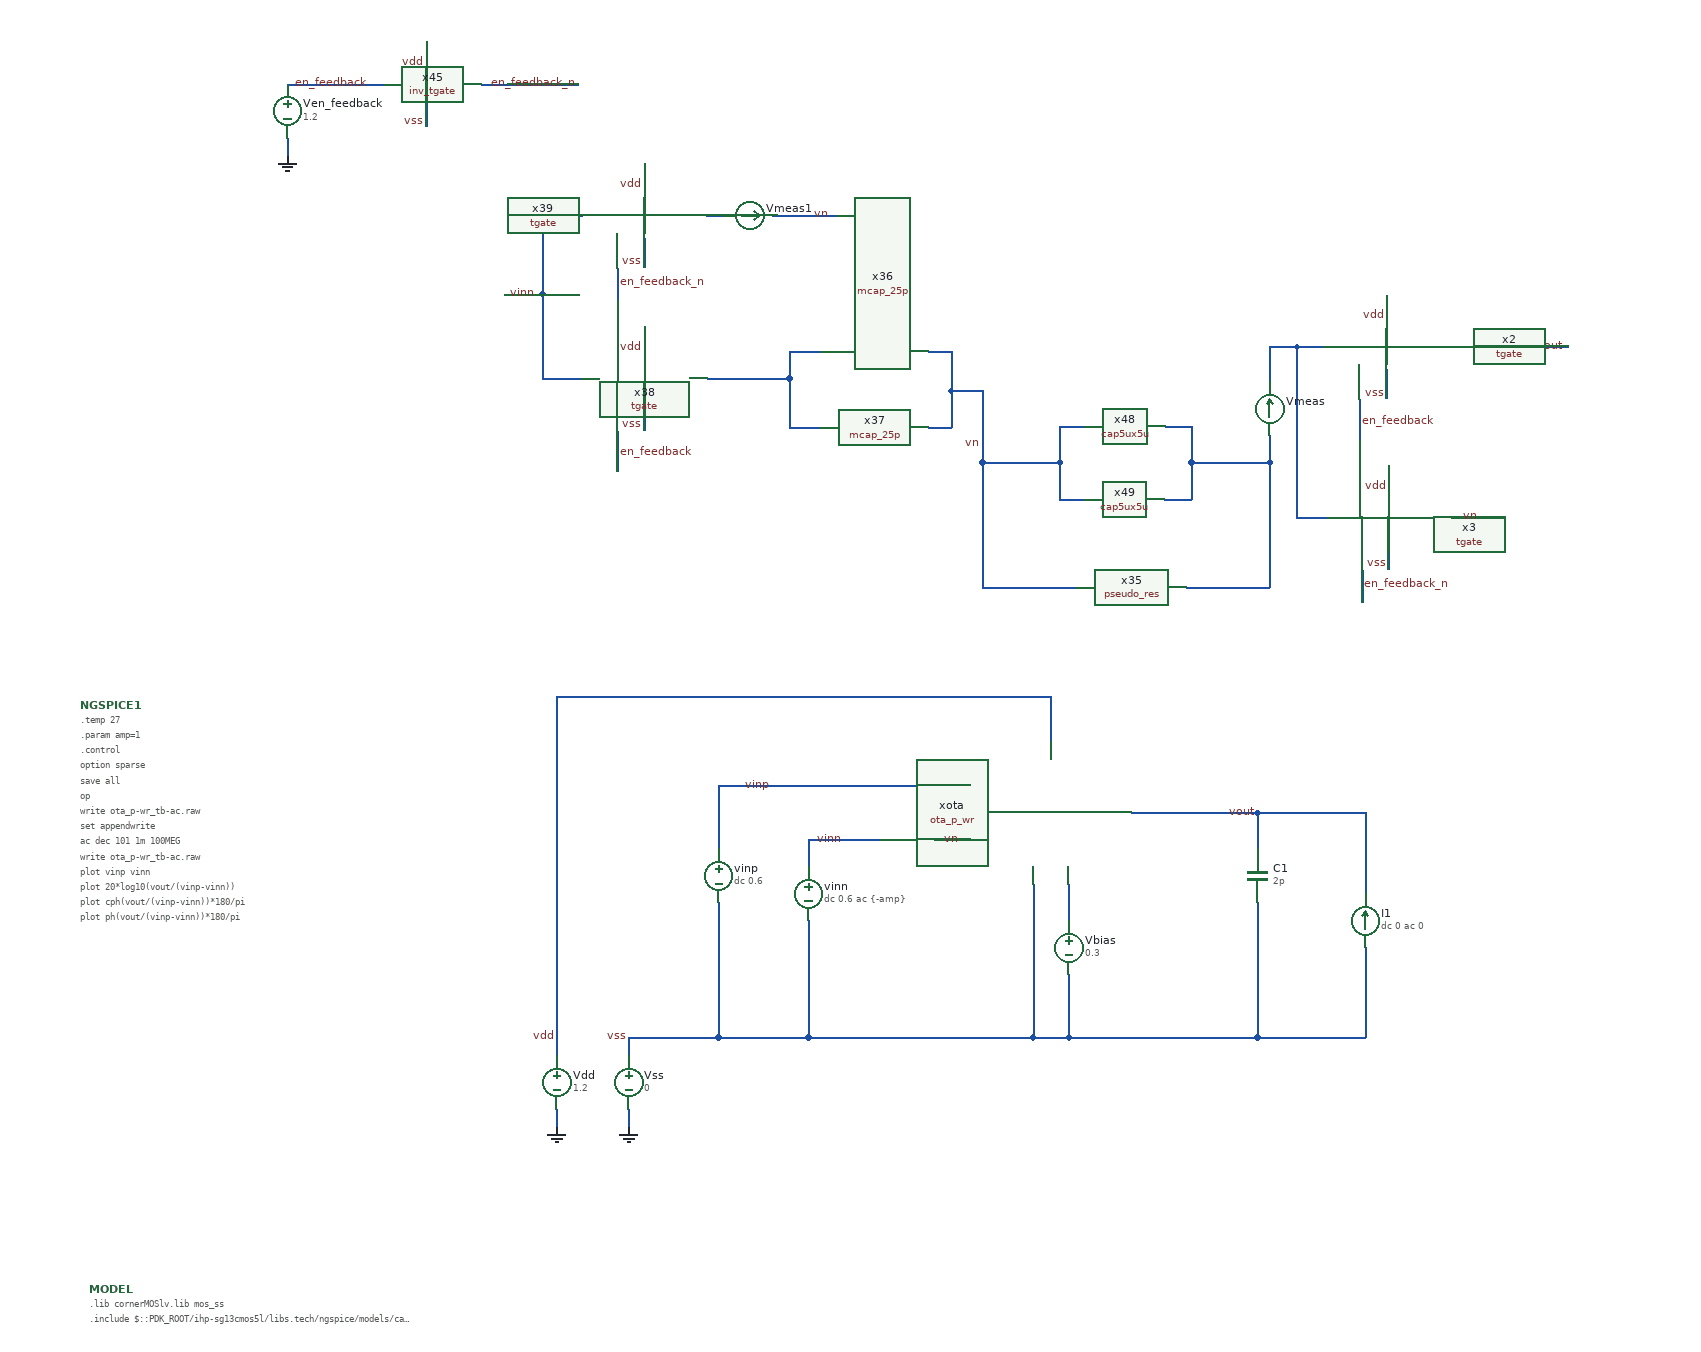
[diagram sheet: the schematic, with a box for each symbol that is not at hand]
v {xschem version=3.4.8RC file_version=1.3}
G {}
K {}
V {}
S {}
F {}
E {}
N 520 -300 520 -280 {
lab=GND}
N 600 -300 600 -280 {
lab=GND}
N 600 -380 600 -360 {
lab=vss}
N 1050 -550 1050 -380 {
lab=vss}
N 1300 -530 1300 -380 {
lab=vss}
N 1300 -630 1300 -590 {
lab=vout}
N 800 -600 880 -600 {
lab=vinn}
N 1070 -760 1070 -710 {
lab=vdd}
N 520 -760 1070 -760 {
lab=vdd}
N 520 -760 520 -360 {
lab=vdd}
N 1420 -480 1420 -380 {lab=vss}
N 1300 -380 1420 -380 {lab=vss}
N 1420 -630 1420 -540 {lab=vout}
N 1300 -630 1420 -630 {lab=vout}
N 800 -380 1050 -380 {
lab=vss}
N 800 -600 800 -570 {lab=vinn}
N 800 -510 800 -380 {lab=vss}
N 1090 -550 1090 -510 {lab=#net1}
N 1090 -380 1300 -380 {
lab=vss}
N 1090 -450 1090 -380 {
lab=vss}
N 1050 -380 1090 -380 {
lab=vss}
N 1160 -630 1300 -630 {lab=vout}
N 700 -660 980 -660 {lab=vinp}
N 700 -660 700 -590 {lab=vinp}
N 700 -530 700 -380 {lab=vss}
N 600 -380 700 -380 {
lab=vss}
N 700 -380 800 -380 {
lab=vss}
N 940 -600 980 -600 {lab=vn}
N 778.75 -1058.75 813.75 -1058.75 {lab=#net2}
N 933.75 -1058.75 958.75 -1058.75 {lab=vn}
N 933.75 -1143.75 958.75 -1143.75 {lab=vn}
N 778.75 -1113.75 778.75 -1058.75 {lab=#net2}
N 778.75 -1143.75 778.75 -1113.75 {lab=#net2}
N 993.75 -881.25 1098.75 -881.25 {lab=vn}
N 1221.25 -881.25 1313.75 -881.25 {lab=#net3}
N 1313.75 -1020 1313.75 -881.25 {lab=#net3}
N 993.75 -1020 993.75 -881.25 {lab=vn}
N 958.75 -1100 993.75 -1100 {lab=vn}
N 958.75 -1100 958.75 -1058.75 {lab=vn}
N 958.75 -1143.75 958.75 -1100 {lab=vn}
N 503.75 -1295 548.75 -1295 {lab=vinn}
N 503.75 -1207.5 503.75 -1113.75 {lab=vinn}
N 503.75 -1113.75 547.5 -1113.75 {lab=vinn}
N 461.25 -1207.5 503.75 -1207.5 {lab=vinn}
N 503.75 -1295 503.75 -1207.5 {lab=vinn}
N 587.5 -1236.25 587.5 -1200 {lab=en_feedback_n}
N 587.5 -1055 587.5 -1010 {lab=en_feedback}
N 617.5 -1088.75 617.5 -1056.25 {lab=vss}
N 617.5 -1171.25 617.5 -1138.75 {lab=vdd}
N 617.5 -1270 617.5 -1237.5 {lab=vss}
N 617.5 -1352.5 617.5 -1320 {lab=vdd}
N 220 -1441.25 327.5 -1441.25 {lab=en_feedback}
N 436.25 -1441.25 543.75 -1441.25 {lab=en_feedback_n}
N 375 -1488.75 375 -1456.25 {lab=vdd}
N 375 -1426.25 375 -1393.75 {lab=vss}
N 1197.5 -1060 1226.25 -1060 {lab=#net3}
N 1226.25 -1020 1226.25 -978.75 {lab=#net3}
N 1196.25 -978.75 1226.25 -978.75 {lab=#net3}
N 1080 -978.75 1107.5 -978.75 {lab=vn}
N 1080 -1020 1080 -978.75 {lab=vn}
N 1080 -1060 1107.5 -1060 {lab=vn}
N 1226.25 -1060 1226.25 -1020 {lab=#net3}
N 1080 -1060 1080 -1020 {lab=vn}
N 993.75 -1100 993.75 -1020 {lab=vn}
N 220 -1381.25 220 -1361.25 {
lab=GND}
N 993.75 -1020 1080 -1020 {lab=vn}
N 1226.25 -1020 1313.75 -1020 {lab=#net3}
N 760 -1295 831.25 -1295 {lab=vn}
N 686.25 -1295 705 -1295 {lab=#net4}
N 687.5 -1113.75 778.75 -1113.75 {lab=#net2}
N 1413.75 -1090 1413.75 -1045 {lab=en_feedback}
N 1443.75 -1123.75 1443.75 -1091.25 {lab=vss}
N 1443.75 -1206.25 1443.75 -1173.75 {lab=vdd}
N 1313.75 -1050 1313.75 -1020 {lab=#net3}
N 1343.75 -1148.75 1373.75 -1148.75 {lab=#net5}
N 1313.75 -1148.75 1313.75 -1110 {lab=#net5}
N 1513.75 -1148.75 1646.25 -1148.75 {lab=vout}
N 1416.25 -900 1416.25 -863.75 {lab=en_feedback_n}
N 1446.25 -933.75 1446.25 -901.25 {lab=vss}
N 1446.25 -1016.25 1446.25 -983.75 {lab=vdd}
N 1343.75 -958.75 1377.5 -958.75 {lab=#net5}
N 1343.75 -1148.75 1343.75 -958.75 {lab=#net5}
N 1313.75 -1148.75 1343.75 -1148.75 {lab=#net5}
N 1516.25 -958.75 1555 -958.75 {lab=vn}
N 778.75 -1143.75 813.75 -1143.75 {lab=#net2}
C {devices/code_shown.sym} 0 -100 0 0 {name=MODEL only_toplevel=true
format="tcleval( @value )"
value=".lib cornerMOSlv.lib mos_ss
.include $::PDK_ROOT/ihp-sg13cmos5l/libs.tech/ngspice/models/cap_mfringe.lib
"}
C {devices/vsource.sym} 520 -330 0 0 {name=Vdd value=1.2}
C {devices/gnd.sym} 520 -280 0 0 {name=l3 lab=GND}
C {devices/title.sym} 160 -30 0 0 {name=l5 author="(c) 2024-2025 Harald Pretl, Apache-2.0 license"}
C {devices/launcher.sym} 680 -160 0 0 {name=h2
descr="simulate" 
tclcommand="xschem save; xschem netlist; xschem simulate"
}
C {devices/launcher.sym} 920 -160 0 0 {name=h3
descr="annotate OP" 
tclcommand="set show_hidden_texts 1; xschem annotate_op"
}
C {devices/lab_pin.sym} 520 -380 0 0 {name=p2 sig_type=std_logic lab=vdd}
C {ota_p_wr.sym} 1050 -630 0 0 {name=xota}
C {devices/vsource.sym} 600 -330 0 0 {name=Vss value=0}
C {devices/gnd.sym} 600 -280 0 0 {name=l1 lab=GND}
C {devices/lab_pin.sym} 600 -380 0 0 {name=p1 sig_type=std_logic lab=vss}
C {devices/capa.sym} 1300 -560 0 0 {name=C1
value=2p}
C {devices/lab_wire.sym} 1300 -630 0 0 {name=p3 sig_type=std_logic lab=vout}
C {devices/lab_wire.sym} 760 -660 0 0 {name=p4 sig_type=std_logic lab=vinp}
C {devices/spice_probe.sym} 820 -660 0 0 {name=p5 attrs=""}
C {devices/spice_probe.sym} 1180 -630 0 0 {name=p6 attrs=""}
C {isource.sym} 1420 -510 2 0 {name=I1 value="dc 0 ac 0"}
C {devices/lab_wire.sym} 840 -600 0 0 {name=p7 sig_type=std_logic lab=vinn}
C {devices/code_shown.sym} -10 -750 0 0 {name=NGSPICE1 only_toplevel=true 
value="
.temp 27
.param amp=1
.control
option sparse
save all
op
write ota_p-wr_tb-ac.raw
set appendwrite

ac dec 101 1m 100MEG
write ota_p-wr_tb-ac.raw
plot vinp vinn
plot 20*log10(vout/(vinp-vinn))
plot cph(vout/(vinp-vinn))*180/pi
plot ph(vout/(vinp-vinn))*180/pi

meas ac dcgain MAX vmag(vout) FROM=1m TO=100k
*let f3db = dcgain/sqrt(2)
*meas ac fbw WHEN vmag(vout)=f3db FALL=1
*let gainerror=(dcgain-1)/1
*print 20*log10(dcgain)
*print gaindb
*print fbw
*print gainerror

noise v(vout) v(vinp) dec 101 1m 1MEG
print onoise_total
print inoise_total


.endc
"}
C {devices/vsource.sym} 800 -540 0 0 {name=vinn value="dc 0.6 ac \{-amp\}"}
C {devices/vsource.sym} 1090 -480 0 0 {name=Vbias value=0.3}
C {devices/vsource.sym} 700 -560 0 0 {name=vinp value="dc 0.6"}
C {devices/lab_wire.sym} 970 -600 0 0 {name=p8 sig_type=std_logic lab=vn}
C {pseudo_res.sym} 1153.75 -883.75 0 0 {name=x35}
C {mcap_25p.sym} 873.75 -1148.75 3 0 {name=x36}
C {mcap_25p.sym} 873.75 -1063.75 3 0 {name=x37}
C {lab_wire.sym} 1642.5 -1148.75 0 0 {name=p124 sig_type=std_logic lab=vout
}
C {tgate.sym} 617.5 -1111.25 0 0 {name=x38}
C {tgate.sym} 617.5 -1292.5 0 0 {name=x39}
C {lab_wire.sym} 993.75 -1040 1 0 {name=p123 sig_type=std_logic lab=vn
}
C {lab_wire.sym} 825 -1295 0 0 {name=p125 sig_type=std_logic lab=vn
}
C {lab_wire.sym} 587.5 -1030 2 0 {name=p130 sig_type=std_logic lab=en_feedback}
C {lab_wire.sym} 587.5 -1220 2 0 {name=p131 sig_type=std_logic lab=en_feedback_n}
C {lab_wire.sym} 617.5 -1147.5 1 0 {name=p138 sig_type=std_logic lab=vdd
}
C {lab_wire.sym} 617.5 -1061.25 1 0 {name=p139 sig_type=std_logic lab=vss
}
C {lab_wire.sym} 617.5 -1328.75 1 0 {name=p140 sig_type=std_logic lab=vdd
}
C {lab_wire.sym} 617.5 -1242.5 1 0 {name=p141 sig_type=std_logic lab=vss
}
C {inv_tgate.sym} 367.5 -1440 0 0 {name=x45}
C {lab_wire.sym} 226.25 -1441.25 2 0 {name=p142 sig_type=std_logic lab=en_feedback}
C {lab_wire.sym} 443.75 -1441.25 2 0 {name=p143 sig_type=std_logic lab=en_feedback_n}
C {lab_wire.sym} 375 -1465 1 0 {name=p144 sig_type=std_logic lab=vdd
}
C {lab_wire.sym} 375 -1398.75 1 0 {name=p145 sig_type=std_logic lab=vss
}
C {cap5ux5u.sym} 1157.5 -1060 1 0 {name=x48}
C {cap5ux5u.sym} 1157.5 -978.75 1 0 {name=x49}
C {lab_wire.sym} 465 -1207.5 2 0 {name=p9 sig_type=std_logic lab=vinn
}
C {devices/vsource.sym} 220 -1411.25 0 0 {name=Ven_feedback value=1.2}
C {devices/gnd.sym} 220 -1361.25 0 0 {name=l2 lab=GND}
C {ammeter.sym} 1313.75 -1080 2 0 {name=Vmeas savecurrent=true spice_ignore=0}
C {ammeter.sym} 735 -1295 3 0 {name=Vmeas1 savecurrent=true spice_ignore=0}
C {tgate.sym} 1443.75 -1146.25 0 0 {name=x2}
C {lab_wire.sym} 1413.75 -1065 2 0 {name=p10 sig_type=std_logic lab=en_feedback}
C {lab_wire.sym} 1443.75 -1182.5 1 0 {name=p11 sig_type=std_logic lab=vdd
}
C {lab_wire.sym} 1443.75 -1096.25 1 0 {name=p12 sig_type=std_logic lab=vss
}
C {tgate.sym} 1446.25 -956.25 0 0 {name=x3}
C {lab_wire.sym} 1416.25 -883.75 2 0 {name=p13 sig_type=std_logic lab=en_feedback_n}
C {lab_wire.sym} 1446.25 -992.5 1 0 {name=p14 sig_type=std_logic lab=vdd
}
C {lab_wire.sym} 1446.25 -906.25 1 0 {name=p15 sig_type=std_logic lab=vss
}
C {lab_wire.sym} 1526.25 -958.75 2 0 {name=p16 sig_type=std_logic lab=vn
}
